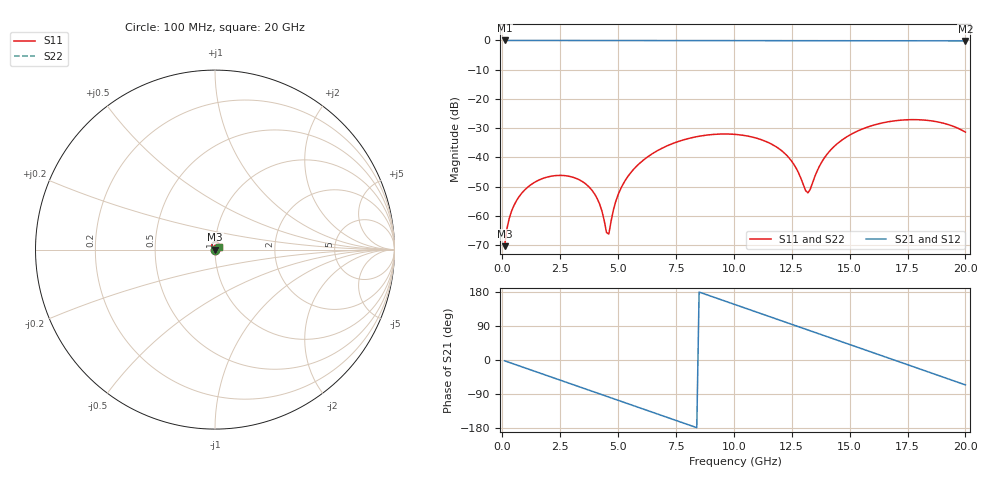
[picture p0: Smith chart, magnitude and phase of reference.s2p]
! circuitRF F0 spike reference -- case B, Palace, LOSSLESS twin (PEC copper, tand 0)
! Palace postpro/port-S.csv, dB/deg -> RI; port 1 excited only; S22 = S11 and S12 = S21 by the 180-degree rotational symmetry of the geometry
# GHz S RI R 50
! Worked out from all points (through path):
!   200 points, 100 MHz to 20 GHz, reference 50 ohm
!   highest |S21| = 0.00 dB at 100 MHz (marker M1); lowest = -0.1 dB at 20 GHz (marker M2)
!   group delay of S21, straight-line fit = 59.1 ps
!   lowest |S11| = -70.3 dB at 100 MHz (marker M3), VSWR 1.00, Z = 50 + j0.0304 ohm
!   |S11| at or under -10 dB: start of sweep to end of sweep
!   |S22| runs from -70.3 to -27.1 dB; largest |S21 - S12| = 0
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0.1  1.15e-05 0.000304  0.9993 -0.0371  0.9993 -0.0371  1.15e-05 0.000304
0.2  4.6e-05 0.000605  0.9972 -0.0741  0.9972 -0.0741  4.6e-05 0.000605
0.4  0.000182 0.00119  0.989 -0.1479  0.989 -0.1479  0.000182 0.00119
1.1  0.00126 0.00284  0.9178 -0.3969  0.9178 -0.3969  0.00126 0.00284
2.3  0.00377 0.00311  0.6571 -0.7533  0.6571 -0.7533  0.00377 0.00311
3.5  0.0037 0.00073  0.2684 -0.9624  0.2684 -0.9624  0.0037 0.00073
4.1  0.00196 -0.000284  0.0492 -0.9975  0.0492 -0.9975  0.00196 -0.000284
4.6  -0.000245 -0.000424  -0.1357 -0.9891  -0.1357 -0.9891  -0.000245 -0.000424
4.9  -0.00177 -6.32e-05  -0.2447 -0.9677  -0.2447 -0.9677  -0.00177 -6.32e-05
5.3  -0.00385 0.00102  -0.385 -0.9205  -0.385 -0.9205  -0.00385 0.00102
6.8  -0.00845 0.0108  -0.8121 -0.5772  -0.8121 -0.5772  -0.00845 0.0108
8.4  -0.000978 0.0226  -0.994 -0.0242  -0.994 -0.0242  -0.000978 0.0226
10.1  0.0142 0.0202  -0.8155 0.5653  -0.8155 0.5653  0.0142 0.0202
11.8  0.015 0.00379  -0.3247 0.9359  -0.3247 0.9359  0.015 0.00379
12.5  0.0085 -0.00126  -0.0732 0.9873  -0.0732 0.9873  0.0085 -0.00126
13.2  -0.000441 -0.00244  0.1831 0.9724  0.1831 0.9724  -0.000441 -0.00244
13.4  -0.00315 -0.00191  0.2547 0.9559  0.2547 0.9559  -0.00315 -0.00191
13.9  -0.00962 0.00118  0.4268 0.892  0.4268 0.892  -0.00962 0.00118
14.5  -0.0158 0.00787  0.6132 0.775  0.6132 0.775  -0.0158 0.00787
16.7  -0.00861 0.04  0.9827 0.0817  0.9827 0.0817  -0.00861 0.04
18.3  0.0159 0.0402  0.8583 -0.4832  0.8583 -0.4832  0.0159 0.0402
20  0.0217 0.0162  0.4048 -0.8976  0.4048 -0.8976  0.0217 0.0162
